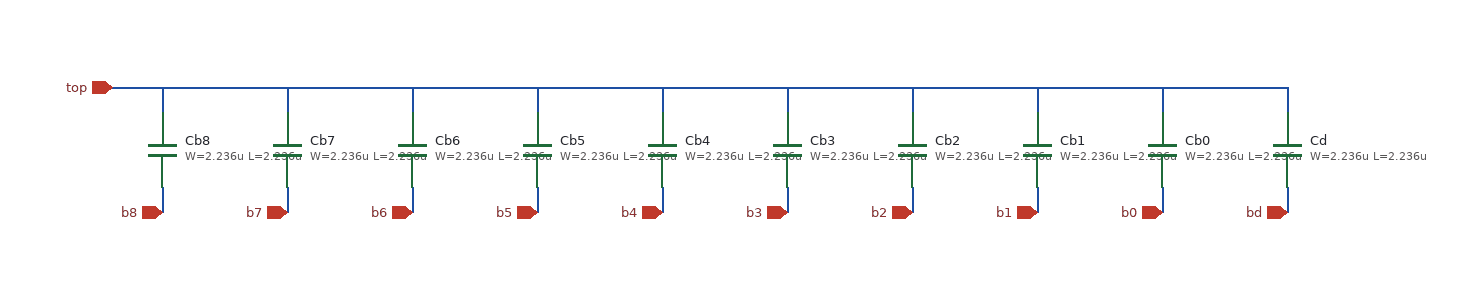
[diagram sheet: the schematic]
v {xschem version=3.4.8RC file_version=1.3}
G {}
K {}
V {}
S {}
F {}
E {}
N 100 -250 100 -230 {lab=top}
N 200 -250 200 -230 {lab=top}
N 300 -250 300 -230 {lab=top}
N 400 -250 400 -230 {lab=top}
N 500 -250 500 -230 {lab=top}
N 600 -250 600 -230 {lab=top}
N 700 -250 700 -230 {lab=top}
N 800 -250 800 -230 {lab=top}
N 900 -250 900 -230 {lab=top}
N 1000 -250 1000 -230 {lab=top}
N 60 -250 1000 -250 {lab=top}
N 100 -170 100 -150 {lab=b8}
N 200 -170 200 -150 {lab=b7}
N 300 -170 300 -150 {lab=b6}
N 400 -170 400 -150 {lab=b5}
N 500 -170 500 -150 {lab=b4}
N 600 -170 600 -150 {lab=b3}
N 700 -170 700 -150 {lab=b2}
N 800 -170 800 -150 {lab=b1}
N 900 -170 900 -150 {lab=b0}
N 1000 -170 1000 -150 {lab=bd}
C {symbols/cap_mim_2f0fF.sym} 100 -200 0 0 {name=Cb8
W=2.236u
L=2.236u
model=cap_mim_2f0fF
spiceprefix=X
m=256}
C {symbols/cap_mim_2f0fF.sym} 200 -200 0 0 {name=Cb7
W=2.236u
L=2.236u
model=cap_mim_2f0fF
spiceprefix=X
m=128}
C {symbols/cap_mim_2f0fF.sym} 300 -200 0 0 {name=Cb6
W=2.236u
L=2.236u
model=cap_mim_2f0fF
spiceprefix=X
m=64}
C {symbols/cap_mim_2f0fF.sym} 400 -200 0 0 {name=Cb5
W=2.236u
L=2.236u
model=cap_mim_2f0fF
spiceprefix=X
m=32}
C {symbols/cap_mim_2f0fF.sym} 500 -200 0 0 {name=Cb4
W=2.236u
L=2.236u
model=cap_mim_2f0fF
spiceprefix=X
m=16}
C {symbols/cap_mim_2f0fF.sym} 600 -200 0 0 {name=Cb3
W=2.236u
L=2.236u
model=cap_mim_2f0fF
spiceprefix=X
m=8}
C {symbols/cap_mim_2f0fF.sym} 700 -200 0 0 {name=Cb2
W=2.236u
L=2.236u
model=cap_mim_2f0fF
spiceprefix=X
m=4}
C {symbols/cap_mim_2f0fF.sym} 800 -200 0 0 {name=Cb1
W=2.236u
L=2.236u
model=cap_mim_2f0fF
spiceprefix=X
m=2}
C {symbols/cap_mim_2f0fF.sym} 900 -200 0 0 {name=Cb0
W=2.236u
L=2.236u
model=cap_mim_2f0fF
spiceprefix=X
m=1}
C {symbols/cap_mim_2f0fF.sym} 1000 -200 0 0 {name=Cd
W=2.236u
L=2.236u
model=cap_mim_2f0fF
spiceprefix=X
m=1}
C {iopin.sym} 60 -250 2 0 {name=p_top lab=top}
C {iopin.sym} 100 -150 1 0 {name=p_b8 lab=b8}
C {iopin.sym} 200 -150 1 0 {name=p_b7 lab=b7}
C {iopin.sym} 300 -150 1 0 {name=p_b6 lab=b6}
C {iopin.sym} 400 -150 1 0 {name=p_b5 lab=b5}
C {iopin.sym} 500 -150 1 0 {name=p_b4 lab=b4}
C {iopin.sym} 600 -150 1 0 {name=p_b3 lab=b3}
C {iopin.sym} 700 -150 1 0 {name=p_b2 lab=b2}
C {iopin.sym} 800 -150 1 0 {name=p_b1 lab=b1}
C {iopin.sym} 900 -150 1 0 {name=p_b0 lab=b0}
C {iopin.sym} 1000 -150 1 0 {name=p_bd lab=bd}
C {title.sym} 160 -40 0 0 {name=l1 author="Gilang Fajrul Falah"}
